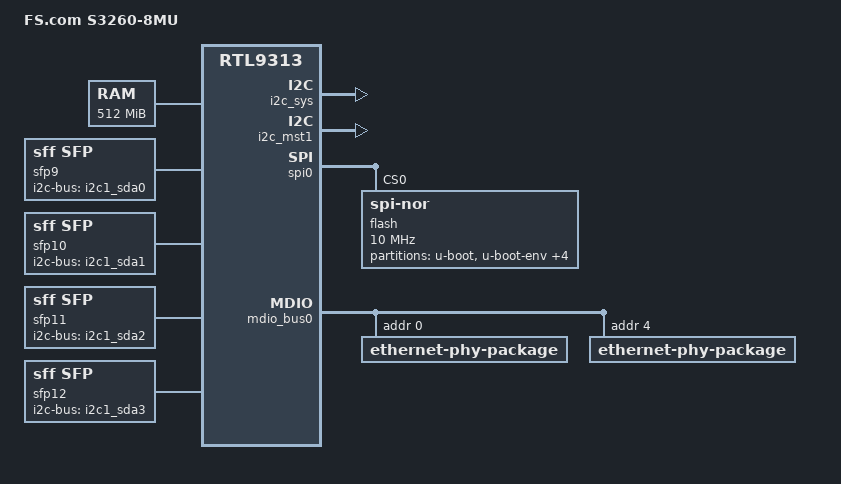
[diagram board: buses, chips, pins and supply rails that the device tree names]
// SPDX-License-Identifier: GPL-2.0-or-later
/dts-v1/;

#include "rtl931x.dtsi"

#include <dt-bindings/input/input.h>
#include <dt-bindings/gpio/gpio.h>
#include <dt-bindings/leds/common.h>
#include <dt-bindings/phy/phy.h>

/ {
	compatible = "fscom,s3260-8mu", "realtek,rtl9313-soc";
	model = "FS.com S3260-8MU";

	memory@0 {
		device_type = "memory";
		reg = <0x00000000 0x10000000>, /* 256 MiB lowmem */
		      <0x90000000 0x10000000>; /* 256 MiB highmem */
	};

	chosen {
		stdout-path = "serial0:115200n8";
	};

	sfp9: sfp-p9 {
		compatible = "sff,sfp";
		i2c-bus = <&i2c1_sda0>;
	};

	sfp10: sfp-p10 {
		compatible = "sff,sfp";
		i2c-bus = <&i2c1_sda1>;
	};

	sfp11: sfp-p11 {
		compatible = "sff,sfp";
		i2c-bus = <&i2c1_sda2>;
	};

	sfp12: sfp-p12 {
		compatible = "sff,sfp";
		i2c-bus = <&i2c1_sda3>;
	};

	i2c_sys: i2c-system {
		compatible = "i2c-gpio";
		#address-cells = <1>;
		#size-cells = <0>;

		// tried:
		// 5+4 4+5
		// 8+7 7+8
		// TODO: try with i2c-gpio,delay-us
		// scl-gpios = <&gpio0 7 (GPIO_ACTIVE_HIGH | GPIO_OPEN_DRAIN)>;
		// sda-gpios = <&gpio0 8 (GPIO_ACTIVE_HIGH | GPIO_OPEN_DRAIN)>;
	};
};

// line 3 is reset button
// line 6 is led-mode button
&gpio0 {
	pinctrl-names = "default";
	pinctrl-0 = <&pinmux_disable_jtag>;
};

&i2c_mst1 {
	status = "okay";

	i2c1_sda0: i2c@0 { reg = <0>; };
	i2c1_sda1: i2c@1 { reg = <1>; };
	i2c1_sda2: i2c@2 { reg = <2>; };
	i2c1_sda3: i2c@3 { reg = <3>; };
};

&spi0 {
	status = "okay";

	flash@0 {
		compatible = "jedec,spi-nor";
		reg = <0>;
		spi-max-frequency = <10000000>;

		partitions {
			compatible = "fixed-partitions";
			#address-cells = <1>;
			#size-cells = <1>;

			/* stock is LOADER */
			partition@0 {
				label = "u-boot";
				reg = <0x0000000 0x0400000>; // 4M
				read-only;
			};

			/* stock is BDINFO */
			partition@400000 {
				label = "u-boot-env";
				reg = <0x0400000 0x0080000>; // 512K
			};

			/* stock is SYSINFO */
			partition@480000 {
				label = "u-boot-env2";
				reg = <0x0480000 0x0080000>; // 512K
			};

			/* stock is CFG JFFS2 */
			partition@500000 {
				label = "jffs";
				reg = <0x0500000 0x0100000>; // 1M
			};

			/* stock is LOG JFFS2 */
			partition@600000 {
				label = "jffs2";
				reg = <0x0600000 0x0c00000>; // 12M
			};

			/* stock is RUNTIME and RUNTIME2
			 * RUNTIME is <0x1200000 0x1700000>
			 * RUNTIME2 is <0x2900000 0x1700000>
			 */
			partition@1200000 {
				compatible = "openwrt,uimage", "denx,uimage";
				label = "firmware";
				reg = <0x1200000 0x2e00000>; // 46M
			};
		};
	};
};

&mdio_bus0 {
	ethernet-phy-package@0 {
		#address-cells = <1>;
		#size-cells = <0>;
		reg = <0>;

		PHY_C45(0, 0)
		PHY_C45(1, 1)
		PHY_C45(4, 2)
		PHY_C45(5, 3)
	};

	ethernet-phy-package@4 {
		#address-cells = <1>;
		#size-cells = <0>;
		reg = <4>;

		PHY_C45(8, 4)
		PHY_C45(9, 5)
		PHY_C45(12, 6)
		PHY_C45(13, 7)
	};
};

&switch0 {
	ethernet-ports {
		#address-cells = <1>;
		#size-cells = <0>;

		SWITCH_PORT_SDS(0, 1, 2, 0, 10g-qxgmii)
		SWITCH_PORT_SDS(1, 2, 2, 1, 10g-qxgmii)
		SWITCH_PORT_SDS(4, 3, 2, 2, 10g-qxgmii)
		SWITCH_PORT_SDS(5, 4, 2, 3, 10g-qxgmii)

		SWITCH_PORT_SDS(8, 5, 3, 0, 10g-qxgmii)
		SWITCH_PORT_SDS(9, 6, 3, 1, 10g-qxgmii)
		SWITCH_PORT_SDS(12, 7, 3, 2, 10g-qxgmii)
		SWITCH_PORT_SDS(13, 8, 3, 3, 10g-qxgmii)

		SWITCH_PORT_SFP(52, 9, 10, 3, 9)
		SWITCH_PORT_SFP(53, 10,  11, 3, 10)
		SWITCH_PORT_SFP(54, 11, 12, 3, 11)
		SWITCH_PORT_SFP(55, 12, 13, 3, 12)

		/* CPU port */
		port@56 {
			ethernet = <&ethernet0>;
			reg = <56>;
			phy-mode = "internal";
			fixed-link {
				speed = <1000>;
				full-duplex;
			};
		};
	};
};

&serdes10 {
	tx-polarity = <PHY_POL_INVERT>;
};
&serdes11 {
	tx-polarity = <PHY_POL_INVERT>;
};
&serdes12 {
	tx-polarity = <PHY_POL_INVERT>;
};
&serdes13 {
	tx-polarity = <PHY_POL_INVERT>;
};
